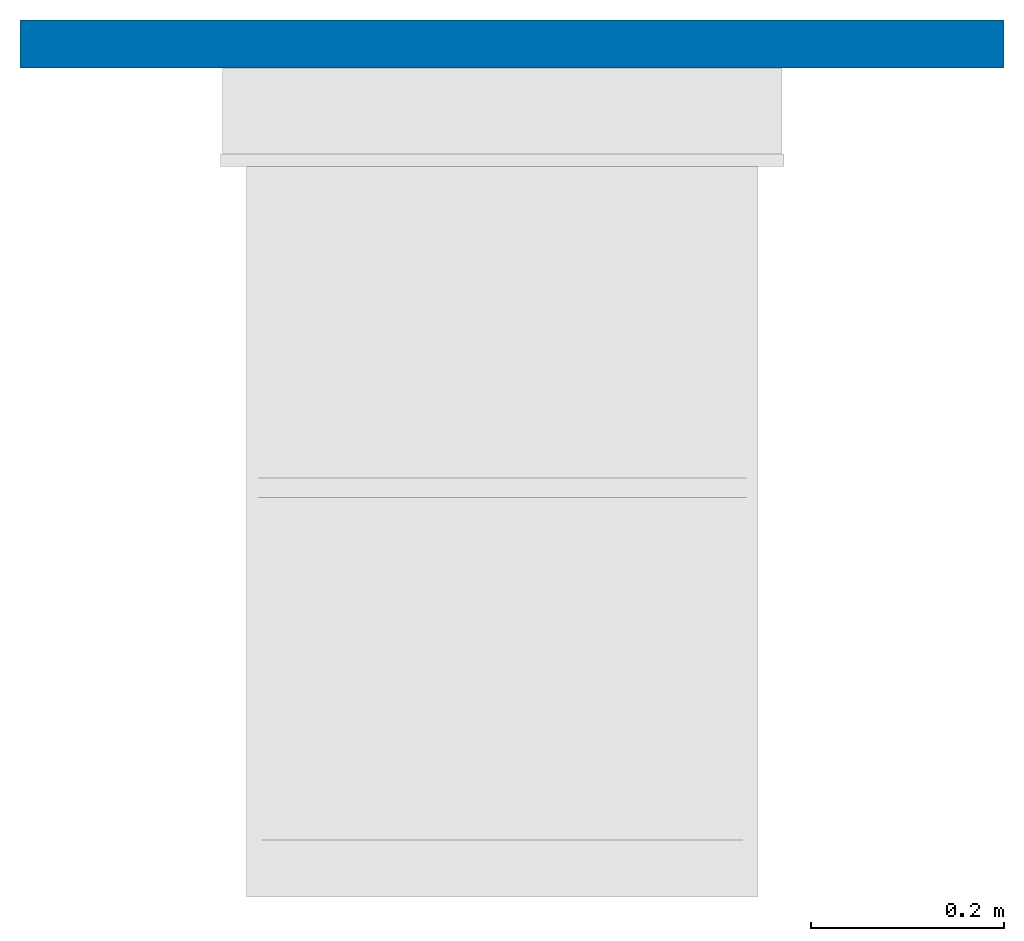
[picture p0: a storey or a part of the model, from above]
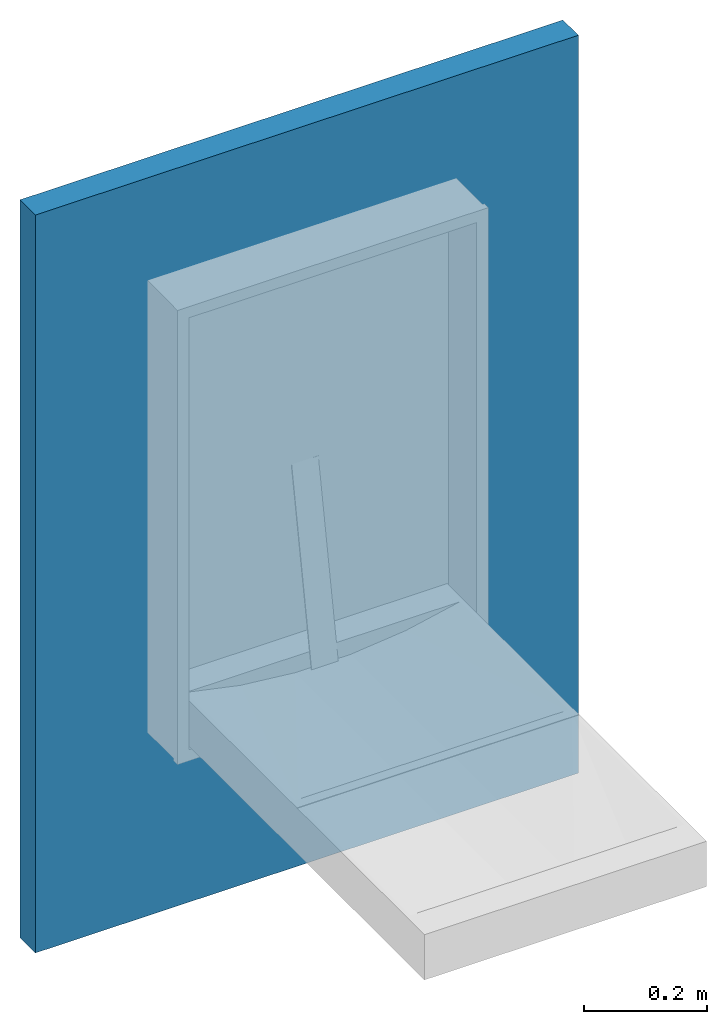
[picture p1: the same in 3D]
Properties of the parts of a building model (IFC2X3)

# File
Description: ViewDefinition [CoordinationView]
Time: 2016-11-02T10:05:35
Written by: The EXPRESS Data Manager Version 5.01.0100.02.64mod : 6 Jun 2012
Made in: 20140709_2115(x64) - Exporter 2014.0.2014.0709 - Default UI
Comment: STEP Physical File produced by: The EXPRESS Data Manager Version 5.01.0100.02.64mod : 6 Jun 2012 * Module: EDMstepFileFactory/EDMstandAlone * Creation date: Wed Nov 02 10:05:35 2016 * Host: BIM-HP * Database: C:\Users\dcole\AppData\Local\Temp\{FE4BBD0D-C1AA-4A29-A620-3D216B685319}\ifc * Database version: 5507 * Database creation date: Wed Nov 02 10:05:33 2016 * Schema: IFC2X3 * Model: DataRepository.ifc * Model creation date: Wed Nov 02 10:05:34 2016 * Header model: DataRepository.ifc_HeaderModel * Header model creation date: Wed Nov 02 10:05:34 2016 * EDMuser: sdai-user * EDMgroup: sdai-group * License ID and type: 5605 : Permanent license. Expiry date: * EDMstepFileFactory options: 020000

# IfcProject
LongName: P:\Fastrack\53721_BELL-CHEM\ADDITIONAL DRAWINGS 2016 BIM\IFC\BC100SV-SM.ifc

# IfcSite, Default
RefLatitude: 42, 24, 53, 508911; RefLongitude: -71, -15, -29, -58837; RefElevation: 0 mm

# IfcBuilding
Pset_BuildingCommon - NumberOfStoreys: 1

# IfcBuildingStorey, Level 1
LongName: Level 1; Elevation: 0 mm
Constraints - Elevation Base: Project Base Point; Elevation: 0 mm
Identity Data - Building Story: yes; Structural: no; Name: Level 1
Dimensions - Computation Height: 0 mm
Graphics - Symbol at End 1 Default: no; Color: 0; Line Weight: 1; Line Pattern: -3000010; Symbol at End 2 Default: yes

# IfcBuildingElementProxy: BC100SV-SM Dolphin Vertical Stainless Steel Nappy Changing Unit, BC100SV-SM:BC100SV-SM Dolphin Vertical Stainless Steel Nappy Changing Unit:29326
In: Level 1
Material: Black Rubber Stop, Plastic Insert, Stainless Steel
Dimensions - Volume: 0.0425088 m3; Height: 902mm; Projection: Closed = 102mm Open = 859mm; Width: 584mm
Constraints - Host: Level : Level 1; Moves With Nearby Elements: no; Level: Level: Level 1; Offset: -412.086 mm
Phasing - Phase Created: New Construction
Pset_ManufacturerTypeInformation - Manufacturer: Dolphin Solutions Ltd.
Pset_BuildingElementProxyCommon - Reference: BC100SV-SM Dolphin Vertical Stainless Steel Nappy Changing Unit
Identity Data - URL: www.dolphinsolutions.co.uk; Fax No.: +44 (0) 1424 205 200; Manufacturer: Dolphin Solutions Ltd.; Tel No.: +44 (0) 1424 202 224; Description: Surface mounted vertical stainless steel nappy changing unit.; Assembly Description: Other Plumbing Fixtures; Email: info@dolphinsolutions.co.uk; Assembly Code: D2010900; Model: BC100SV-SM; Address: Southpoint, Compass Park, Junction Road, Bodiam, TN32 5BS
General - Warranty: 5 years; Product Data: Supports a static load of 181kg. Entire body is 16 gauge, type 304 brushed stainless steel. Both recessed and surface-mounted options available. Full stainless steel frame and hinges provide maximum durability. Concealed pneumatic control cylinder provides smooth opening/closing. 5 year Warranty: This product is warranted against manufacturing defects for a period of 5 years.; Product Page Link: https://www.dolphinsolutions.co.uk/product/surface-mounted-vertical-stainless-steel-nappy-changing-unit/

# IfcWallStandardCase: Basic Wall:Wall 1, Basic Wall:Wall 1:3092
In: Level 1
Type - PredefinedType: STANDARD; Material: Default Wall 50 mm
Type - Construction - Function: Exterior; Wrapping at Inserts: Do not wrap; Width: 50 mm
Type - Graphics - Coarse Scale Fill Color: 8454143
Type - Analytical Properties - Roughness: 1; Absorptance: 0.1
Constraints - Unconnected Height: 1465.65 mm; Location Line: Finish Face: Interior; Base Constraint: Level: Level 1; Top is Attached: no; Base is Attached: no; Room Bounding: yes; Related to Mass: no; Top Offset: 0 mm; Base Offset: -797.123 mm; Top Extension Distance: 0 mm; Base Extension Distance: 0 mm
Phasing - Phase Created: New Construction
Structural - Structural: no; Structural Usage: Non-bearing; Enable Analytical Model: no
Dimensions - Length: 1020 mm; Volume: 0.0747479 m3; Area: 1.49496 m2
Pset_WallCommon - Reference: Wall 1; LoadBearing: no; ExtendToStructure: no; IsExternal: yes
